VERSION 5.7 ;
  NOWIREEXTENSIONATPIN ON ;
  DIVIDERCHAR "/" ;
  BUSBITCHARS "[]" ;
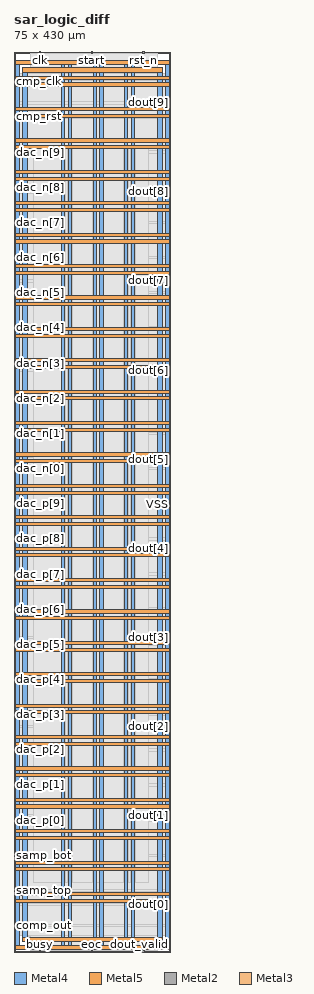
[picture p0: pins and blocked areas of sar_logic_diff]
MACRO sar_logic_diff
  CLASS BLOCK ;
  FOREIGN sar_logic_diff ;
  ORIGIN 0.000 0.000 ;
  SIZE 75.000 BY 430.000 ;
  PIN VDD
    DIRECTION INOUT ;
    USE POWER ;
    PORT
      LAYER Metal4 ;
        RECT 4.280 4.840 6.280 422.440 ;
    END
    PORT
      LAYER Metal4 ;
        RECT 68.760 4.840 70.760 422.440 ;
    END
    PORT
      LAYER Metal5 ;
        RECT 4.280 4.840 70.760 6.840 ;
    END
    PORT
      LAYER Metal5 ;
        RECT 4.280 420.440 70.760 422.440 ;
    END
    PORT
      LAYER Metal4 ;
        RECT 22.850 1.340 24.350 425.940 ;
    END
    PORT
      LAYER Metal4 ;
        RECT 37.850 1.340 39.350 425.940 ;
    END
    PORT
      LAYER Metal4 ;
        RECT 52.850 1.340 54.350 425.940 ;
    END
    PORT
      LAYER Metal5 ;
        RECT 0.780 23.740 74.260 25.240 ;
    END
    PORT
      LAYER Metal5 ;
        RECT 0.780 38.740 74.260 40.240 ;
    END
    PORT
      LAYER Metal5 ;
        RECT 0.780 53.740 74.260 55.240 ;
    END
    PORT
      LAYER Metal5 ;
        RECT 0.780 68.740 74.260 70.240 ;
    END
    PORT
      LAYER Metal5 ;
        RECT 0.780 83.740 74.260 85.240 ;
    END
    PORT
      LAYER Metal5 ;
        RECT 0.780 98.740 74.260 100.240 ;
    END
    PORT
      LAYER Metal5 ;
        RECT 0.780 113.740 74.260 115.240 ;
    END
    PORT
      LAYER Metal5 ;
        RECT 0.780 128.740 74.260 130.240 ;
    END
    PORT
      LAYER Metal5 ;
        RECT 0.780 143.740 74.260 145.240 ;
    END
    PORT
      LAYER Metal5 ;
        RECT 0.780 158.740 74.260 160.240 ;
    END
    PORT
      LAYER Metal5 ;
        RECT 0.780 173.740 74.260 175.240 ;
    END
    PORT
      LAYER Metal5 ;
        RECT 0.780 188.740 74.260 190.240 ;
    END
    PORT
      LAYER Metal5 ;
        RECT 0.780 203.740 74.260 205.240 ;
    END
    PORT
      LAYER Metal5 ;
        RECT 0.780 218.740 74.260 220.240 ;
    END
    PORT
      LAYER Metal5 ;
        RECT 0.780 233.740 74.260 235.240 ;
    END
    PORT
      LAYER Metal5 ;
        RECT 0.780 248.740 74.260 250.240 ;
    END
    PORT
      LAYER Metal5 ;
        RECT 0.780 263.740 74.260 265.240 ;
    END
    PORT
      LAYER Metal5 ;
        RECT 0.780 278.740 74.260 280.240 ;
    END
    PORT
      LAYER Metal5 ;
        RECT 0.780 293.740 74.260 295.240 ;
    END
    PORT
      LAYER Metal5 ;
        RECT 0.780 308.740 74.260 310.240 ;
    END
    PORT
      LAYER Metal5 ;
        RECT 0.780 323.740 74.260 325.240 ;
    END
    PORT
      LAYER Metal5 ;
        RECT 0.780 338.740 74.260 340.240 ;
    END
    PORT
      LAYER Metal5 ;
        RECT 0.780 353.740 74.260 355.240 ;
    END
    PORT
      LAYER Metal5 ;
        RECT 0.780 368.740 74.260 370.240 ;
    END
    PORT
      LAYER Metal5 ;
        RECT 0.780 383.740 74.260 385.240 ;
    END
    PORT
      LAYER Metal5 ;
        RECT 0.780 398.740 74.260 400.240 ;
    END
    PORT
      LAYER Metal5 ;
        RECT 0.780 413.740 74.260 415.240 ;
    END
  END VDD
  PIN VSS
    DIRECTION INOUT ;
    USE GROUND ;
    PORT
      LAYER Metal4 ;
        RECT 0.780 1.340 2.780 425.940 ;
    END
    PORT
      LAYER Metal4 ;
        RECT 72.260 1.340 74.260 425.940 ;
    END
    PORT
      LAYER Metal5 ;
        RECT 0.780 1.340 74.260 3.340 ;
    END
    PORT
      LAYER Metal5 ;
        RECT 0.780 423.940 74.260 425.940 ;
    END
    PORT
      LAYER Metal4 ;
        RECT 26.050 1.340 27.550 425.940 ;
    END
    PORT
      LAYER Metal4 ;
        RECT 41.050 1.340 42.550 425.940 ;
    END
    PORT
      LAYER Metal4 ;
        RECT 56.050 1.340 57.550 425.940 ;
    END
    PORT
      LAYER Metal5 ;
        RECT 0.780 26.940 74.260 28.440 ;
    END
    PORT
      LAYER Metal5 ;
        RECT 0.780 41.940 74.260 43.440 ;
    END
    PORT
      LAYER Metal5 ;
        RECT 0.780 56.940 74.260 58.440 ;
    END
    PORT
      LAYER Metal5 ;
        RECT 0.780 71.940 74.260 73.440 ;
    END
    PORT
      LAYER Metal5 ;
        RECT 0.780 86.940 74.260 88.440 ;
    END
    PORT
      LAYER Metal5 ;
        RECT 0.780 101.940 74.260 103.440 ;
    END
    PORT
      LAYER Metal5 ;
        RECT 0.780 116.940 74.260 118.440 ;
    END
    PORT
      LAYER Metal5 ;
        RECT 0.780 131.940 74.260 133.440 ;
    END
    PORT
      LAYER Metal5 ;
        RECT 0.780 146.940 74.260 148.440 ;
    END
    PORT
      LAYER Metal5 ;
        RECT 0.780 161.940 74.260 163.440 ;
    END
    PORT
      LAYER Metal5 ;
        RECT 0.780 176.940 74.260 178.440 ;
    END
    PORT
      LAYER Metal5 ;
        RECT 0.780 191.940 74.260 193.440 ;
    END
    PORT
      LAYER Metal5 ;
        RECT 0.780 206.940 74.260 208.440 ;
    END
    PORT
      LAYER Metal5 ;
        RECT 0.780 221.940 74.260 223.440 ;
    END
    PORT
      LAYER Metal5 ;
        RECT 0.780 236.940 74.260 238.440 ;
    END
    PORT
      LAYER Metal5 ;
        RECT 0.780 251.940 74.260 253.440 ;
    END
    PORT
      LAYER Metal5 ;
        RECT 0.780 266.940 74.260 268.440 ;
    END
    PORT
      LAYER Metal5 ;
        RECT 0.780 281.940 74.260 283.440 ;
    END
    PORT
      LAYER Metal5 ;
        RECT 0.780 296.940 74.260 298.440 ;
    END
    PORT
      LAYER Metal5 ;
        RECT 0.780 311.940 74.260 313.440 ;
    END
    PORT
      LAYER Metal5 ;
        RECT 0.780 326.940 74.260 328.440 ;
    END
    PORT
      LAYER Metal5 ;
        RECT 0.780 341.940 74.260 343.440 ;
    END
    PORT
      LAYER Metal5 ;
        RECT 0.780 356.940 74.260 358.440 ;
    END
    PORT
      LAYER Metal5 ;
        RECT 0.780 371.940 74.260 373.440 ;
    END
    PORT
      LAYER Metal5 ;
        RECT 0.780 386.940 74.260 388.440 ;
    END
    PORT
      LAYER Metal5 ;
        RECT 0.780 401.940 74.260 403.440 ;
    END
    PORT
      LAYER Metal5 ;
        RECT 0.780 416.940 74.260 418.440 ;
    END
  END VSS
  PIN busy
    DIRECTION OUTPUT ;
    USE SIGNAL ;
    ANTENNADIFFAREA 1.182800 ;
    PORT
      LAYER Metal2 ;
        RECT 12.320 0.000 12.880 0.560 ;
    END
  END busy
  PIN clk
    DIRECTION INPUT ;
    USE SIGNAL ;
    ANTENNAGATEAREA 4.738000 ;
    ANTENNADIFFAREA 0.410400 ;
    PORT
      LAYER Metal2 ;
        RECT 12.320 429.440 12.880 430.000 ;
    END
  END clk
  PIN cmp_clk
    DIRECTION OUTPUT ;
    USE SIGNAL ;
    ANTENNADIFFAREA 1.182800 ;
    PORT
      LAYER Metal3 ;
        RECT 0.000 415.520 0.560 416.080 ;
    END
  END cmp_clk
  PIN cmp_rst
    DIRECTION OUTPUT ;
    USE SIGNAL ;
    ANTENNADIFFAREA 1.182800 ;
    PORT
      LAYER Metal3 ;
        RECT 0.000 398.720 0.560 399.280 ;
    END
  END cmp_rst
  PIN comp_out
    DIRECTION INPUT ;
    USE SIGNAL ;
    ANTENNAGATEAREA 0.396000 ;
    ANTENNADIFFAREA 0.410400 ;
    PORT
      LAYER Metal3 ;
        RECT 0.000 12.320 0.560 12.880 ;
    END
  END comp_out
  PIN dac_n[0]
    DIRECTION OUTPUT ;
    USE SIGNAL ;
    ANTENNADIFFAREA 1.182800 ;
    PORT
      LAYER Metal3 ;
        RECT 0.000 230.720 0.560 231.280 ;
    END
  END dac_n[0]
  PIN dac_n[1]
    DIRECTION OUTPUT ;
    USE SIGNAL ;
    ANTENNADIFFAREA 1.182800 ;
    PORT
      LAYER Metal3 ;
        RECT 0.000 247.520 0.560 248.080 ;
    END
  END dac_n[1]
  PIN dac_n[2]
    DIRECTION OUTPUT ;
    USE SIGNAL ;
    ANTENNADIFFAREA 1.182800 ;
    PORT
      LAYER Metal3 ;
        RECT 0.000 264.320 0.560 264.880 ;
    END
  END dac_n[2]
  PIN dac_n[3]
    DIRECTION OUTPUT ;
    USE SIGNAL ;
    ANTENNADIFFAREA 1.182800 ;
    PORT
      LAYER Metal3 ;
        RECT 0.000 281.120 0.560 281.680 ;
    END
  END dac_n[3]
  PIN dac_n[4]
    DIRECTION OUTPUT ;
    USE SIGNAL ;
    ANTENNADIFFAREA 1.182800 ;
    PORT
      LAYER Metal3 ;
        RECT 0.000 297.920 0.560 298.480 ;
    END
  END dac_n[4]
  PIN dac_n[5]
    DIRECTION OUTPUT ;
    USE SIGNAL ;
    ANTENNADIFFAREA 1.182800 ;
    PORT
      LAYER Metal3 ;
        RECT 0.000 314.720 0.560 315.280 ;
    END
  END dac_n[5]
  PIN dac_n[6]
    DIRECTION OUTPUT ;
    USE SIGNAL ;
    ANTENNADIFFAREA 1.182800 ;
    PORT
      LAYER Metal3 ;
        RECT 0.000 331.520 0.560 332.080 ;
    END
  END dac_n[6]
  PIN dac_n[7]
    DIRECTION OUTPUT ;
    USE SIGNAL ;
    ANTENNADIFFAREA 1.182800 ;
    PORT
      LAYER Metal3 ;
        RECT 0.000 348.320 0.560 348.880 ;
    END
  END dac_n[7]
  PIN dac_n[8]
    DIRECTION OUTPUT ;
    USE SIGNAL ;
    ANTENNADIFFAREA 1.182800 ;
    PORT
      LAYER Metal3 ;
        RECT 0.000 365.120 0.560 365.680 ;
    END
  END dac_n[8]
  PIN dac_n[9]
    DIRECTION OUTPUT ;
    USE SIGNAL ;
    ANTENNADIFFAREA 1.182800 ;
    PORT
      LAYER Metal3 ;
        RECT 0.000 381.920 0.560 382.480 ;
    END
  END dac_n[9]
  PIN dac_p[0]
    DIRECTION OUTPUT ;
    USE SIGNAL ;
    ANTENNADIFFAREA 1.182800 ;
    PORT
      LAYER Metal3 ;
        RECT 0.000 62.720 0.560 63.280 ;
    END
  END dac_p[0]
  PIN dac_p[1]
    DIRECTION OUTPUT ;
    USE SIGNAL ;
    ANTENNADIFFAREA 1.182800 ;
    PORT
      LAYER Metal3 ;
        RECT 0.000 79.520 0.560 80.080 ;
    END
  END dac_p[1]
  PIN dac_p[2]
    DIRECTION OUTPUT ;
    USE SIGNAL ;
    ANTENNADIFFAREA 1.182800 ;
    PORT
      LAYER Metal3 ;
        RECT 0.000 96.320 0.560 96.880 ;
    END
  END dac_p[2]
  PIN dac_p[3]
    DIRECTION OUTPUT ;
    USE SIGNAL ;
    ANTENNADIFFAREA 1.182800 ;
    PORT
      LAYER Metal3 ;
        RECT 0.000 113.120 0.560 113.680 ;
    END
  END dac_p[3]
  PIN dac_p[4]
    DIRECTION OUTPUT ;
    USE SIGNAL ;
    ANTENNADIFFAREA 1.182800 ;
    PORT
      LAYER Metal3 ;
        RECT 0.000 129.920 0.560 130.480 ;
    END
  END dac_p[4]
  PIN dac_p[5]
    DIRECTION OUTPUT ;
    USE SIGNAL ;
    ANTENNADIFFAREA 1.182800 ;
    PORT
      LAYER Metal3 ;
        RECT 0.000 146.720 0.560 147.280 ;
    END
  END dac_p[5]
  PIN dac_p[6]
    DIRECTION OUTPUT ;
    USE SIGNAL ;
    ANTENNADIFFAREA 1.182800 ;
    PORT
      LAYER Metal3 ;
        RECT 0.000 163.520 0.560 164.080 ;
    END
  END dac_p[6]
  PIN dac_p[7]
    DIRECTION OUTPUT ;
    USE SIGNAL ;
    ANTENNADIFFAREA 1.182800 ;
    PORT
      LAYER Metal3 ;
        RECT 0.000 180.320 0.560 180.880 ;
    END
  END dac_p[7]
  PIN dac_p[8]
    DIRECTION OUTPUT ;
    USE SIGNAL ;
    ANTENNADIFFAREA 1.182800 ;
    PORT
      LAYER Metal3 ;
        RECT 0.000 197.120 0.560 197.680 ;
    END
  END dac_p[8]
  PIN dac_p[9]
    DIRECTION OUTPUT ;
    USE SIGNAL ;
    ANTENNADIFFAREA 1.182800 ;
    PORT
      LAYER Metal3 ;
        RECT 0.000 213.920 0.560 214.480 ;
    END
  END dac_p[9]
  PIN dout[0]
    DIRECTION OUTPUT ;
    USE SIGNAL ;
    ANTENNADIFFAREA 1.182800 ;
    PORT
      LAYER Metal3 ;
        RECT 74.440 22.400 75.000 22.960 ;
    END
  END dout[0]
  PIN dout[1]
    DIRECTION OUTPUT ;
    USE SIGNAL ;
    ANTENNADIFFAREA 1.182800 ;
    PORT
      LAYER Metal3 ;
        RECT 74.440 64.960 75.000 65.520 ;
    END
  END dout[1]
  PIN dout[2]
    DIRECTION OUTPUT ;
    USE SIGNAL ;
    ANTENNADIFFAREA 1.182800 ;
    PORT
      LAYER Metal3 ;
        RECT 74.440 107.520 75.000 108.080 ;
    END
  END dout[2]
  PIN dout[3]
    DIRECTION OUTPUT ;
    USE SIGNAL ;
    ANTENNADIFFAREA 1.182800 ;
    PORT
      LAYER Metal3 ;
        RECT 74.440 150.080 75.000 150.640 ;
    END
  END dout[3]
  PIN dout[4]
    DIRECTION OUTPUT ;
    USE SIGNAL ;
    ANTENNADIFFAREA 1.182800 ;
    PORT
      LAYER Metal3 ;
        RECT 74.440 192.640 75.000 193.200 ;
    END
  END dout[4]
  PIN dout[5]
    DIRECTION OUTPUT ;
    USE SIGNAL ;
    ANTENNADIFFAREA 1.182800 ;
    PORT
      LAYER Metal3 ;
        RECT 74.440 235.200 75.000 235.760 ;
    END
  END dout[5]
  PIN dout[6]
    DIRECTION OUTPUT ;
    USE SIGNAL ;
    ANTENNADIFFAREA 1.182800 ;
    PORT
      LAYER Metal3 ;
        RECT 74.440 277.760 75.000 278.320 ;
    END
  END dout[6]
  PIN dout[7]
    DIRECTION OUTPUT ;
    USE SIGNAL ;
    ANTENNADIFFAREA 1.182800 ;
    PORT
      LAYER Metal3 ;
        RECT 74.440 320.320 75.000 320.880 ;
    END
  END dout[7]
  PIN dout[8]
    DIRECTION OUTPUT ;
    USE SIGNAL ;
    ANTENNADIFFAREA 1.182800 ;
    PORT
      LAYER Metal3 ;
        RECT 74.440 362.880 75.000 363.440 ;
    END
  END dout[8]
  PIN dout[9]
    DIRECTION OUTPUT ;
    USE SIGNAL ;
    ANTENNADIFFAREA 1.182800 ;
    PORT
      LAYER Metal3 ;
        RECT 74.440 405.440 75.000 406.000 ;
    END
  END dout[9]
  PIN dout_valid
    DIRECTION OUTPUT ;
    USE SIGNAL ;
    ANTENNADIFFAREA 1.182800 ;
    PORT
      LAYER Metal2 ;
        RECT 61.600 0.000 62.160 0.560 ;
    END
  END dout_valid
  PIN eoc
    DIRECTION OUTPUT ;
    USE SIGNAL ;
    ANTENNADIFFAREA 1.182800 ;
    PORT
      LAYER Metal2 ;
        RECT 36.960 0.000 37.520 0.560 ;
    END
  END eoc
  PIN rst_n
    DIRECTION INPUT ;
    USE SIGNAL ;
    ANTENNAGATEAREA 0.396000 ;
    ANTENNADIFFAREA 0.410400 ;
    PORT
      LAYER Metal2 ;
        RECT 61.600 429.440 62.160 430.000 ;
    END
  END rst_n
  PIN samp_bot
    DIRECTION OUTPUT ;
    USE SIGNAL ;
    ANTENNADIFFAREA 1.182800 ;
    PORT
      LAYER Metal3 ;
        RECT 0.000 45.920 0.560 46.480 ;
    END
  END samp_bot
  PIN samp_top
    DIRECTION OUTPUT ;
    USE SIGNAL ;
    ANTENNADIFFAREA 1.182800 ;
    PORT
      LAYER Metal3 ;
        RECT 0.000 29.120 0.560 29.680 ;
    END
  END samp_top
  PIN start
    DIRECTION INPUT ;
    USE SIGNAL ;
    ANTENNAGATEAREA 0.396000 ;
    ANTENNADIFFAREA 0.410400 ;
    PORT
      LAYER Metal2 ;
        RECT 36.960 429.440 37.520 430.000 ;
    END
  END start
  OBS
      LAYER Nwell ;
        RECT 6.850 7.410 68.190 419.870 ;
      LAYER Metal1 ;
        RECT 7.280 7.540 67.760 419.740 ;
      LAYER Metal2 ;
        RECT 7.980 429.140 12.020 429.440 ;
        RECT 13.180 429.140 36.660 429.440 ;
        RECT 37.820 429.140 61.300 429.440 ;
        RECT 62.460 429.140 68.740 429.440 ;
        RECT 7.980 0.860 68.740 429.140 ;
        RECT 7.980 0.560 12.020 0.860 ;
        RECT 13.180 0.560 36.660 0.860 ;
        RECT 37.820 0.560 61.300 0.860 ;
        RECT 62.460 0.560 68.740 0.860 ;
      LAYER Metal3 ;
        RECT 0.560 416.380 74.440 419.580 ;
        RECT 0.860 415.220 74.440 416.380 ;
        RECT 0.560 406.300 74.440 415.220 ;
        RECT 0.560 405.140 74.140 406.300 ;
        RECT 0.560 399.580 74.440 405.140 ;
        RECT 0.860 398.420 74.440 399.580 ;
        RECT 0.560 382.780 74.440 398.420 ;
        RECT 0.860 381.620 74.440 382.780 ;
        RECT 0.560 365.980 74.440 381.620 ;
        RECT 0.860 364.820 74.440 365.980 ;
        RECT 0.560 363.740 74.440 364.820 ;
        RECT 0.560 362.580 74.140 363.740 ;
        RECT 0.560 349.180 74.440 362.580 ;
        RECT 0.860 348.020 74.440 349.180 ;
        RECT 0.560 332.380 74.440 348.020 ;
        RECT 0.860 331.220 74.440 332.380 ;
        RECT 0.560 321.180 74.440 331.220 ;
        RECT 0.560 320.020 74.140 321.180 ;
        RECT 0.560 315.580 74.440 320.020 ;
        RECT 0.860 314.420 74.440 315.580 ;
        RECT 0.560 298.780 74.440 314.420 ;
        RECT 0.860 297.620 74.440 298.780 ;
        RECT 0.560 281.980 74.440 297.620 ;
        RECT 0.860 280.820 74.440 281.980 ;
        RECT 0.560 278.620 74.440 280.820 ;
        RECT 0.560 277.460 74.140 278.620 ;
        RECT 0.560 265.180 74.440 277.460 ;
        RECT 0.860 264.020 74.440 265.180 ;
        RECT 0.560 248.380 74.440 264.020 ;
        RECT 0.860 247.220 74.440 248.380 ;
        RECT 0.560 236.060 74.440 247.220 ;
        RECT 0.560 234.900 74.140 236.060 ;
        RECT 0.560 231.580 74.440 234.900 ;
        RECT 0.860 230.420 74.440 231.580 ;
        RECT 0.560 214.780 74.440 230.420 ;
        RECT 0.860 213.620 74.440 214.780 ;
        RECT 0.560 197.980 74.440 213.620 ;
        RECT 0.860 196.820 74.440 197.980 ;
        RECT 0.560 193.500 74.440 196.820 ;
        RECT 0.560 192.340 74.140 193.500 ;
        RECT 0.560 181.180 74.440 192.340 ;
        RECT 0.860 180.020 74.440 181.180 ;
        RECT 0.560 164.380 74.440 180.020 ;
        RECT 0.860 163.220 74.440 164.380 ;
        RECT 0.560 150.940 74.440 163.220 ;
        RECT 0.560 149.780 74.140 150.940 ;
        RECT 0.560 147.580 74.440 149.780 ;
        RECT 0.860 146.420 74.440 147.580 ;
        RECT 0.560 130.780 74.440 146.420 ;
        RECT 0.860 129.620 74.440 130.780 ;
        RECT 0.560 113.980 74.440 129.620 ;
        RECT 0.860 112.820 74.440 113.980 ;
        RECT 0.560 108.380 74.440 112.820 ;
        RECT 0.560 107.220 74.140 108.380 ;
        RECT 0.560 97.180 74.440 107.220 ;
        RECT 0.860 96.020 74.440 97.180 ;
        RECT 0.560 80.380 74.440 96.020 ;
        RECT 0.860 79.220 74.440 80.380 ;
        RECT 0.560 65.820 74.440 79.220 ;
        RECT 0.560 64.660 74.140 65.820 ;
        RECT 0.560 63.580 74.440 64.660 ;
        RECT 0.860 62.420 74.440 63.580 ;
        RECT 0.560 46.780 74.440 62.420 ;
        RECT 0.860 45.620 74.440 46.780 ;
        RECT 0.560 29.980 74.440 45.620 ;
        RECT 0.860 28.820 74.440 29.980 ;
        RECT 0.560 23.260 74.440 28.820 ;
        RECT 0.560 22.100 74.140 23.260 ;
        RECT 0.560 13.180 74.440 22.100 ;
        RECT 0.860 12.020 74.440 13.180 ;
        RECT 0.560 7.700 74.440 12.020 ;
      LAYER Metal4 ;
        RECT 9.100 33.130 22.550 385.190 ;
        RECT 24.650 33.130 25.750 385.190 ;
        RECT 27.850 33.130 37.550 385.190 ;
        RECT 39.650 33.130 40.750 385.190 ;
        RECT 42.850 33.130 52.550 385.190 ;
        RECT 54.650 33.130 55.750 385.190 ;
        RECT 57.850 33.130 64.260 385.190 ;
  END
END sar_logic_diff
END LIBRARY

